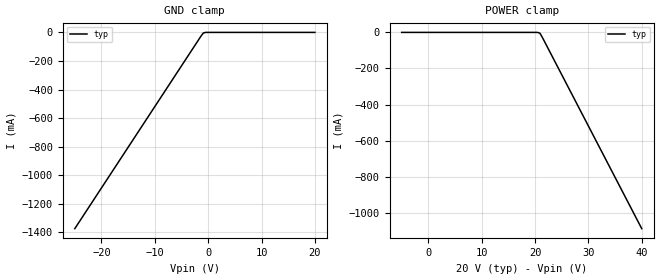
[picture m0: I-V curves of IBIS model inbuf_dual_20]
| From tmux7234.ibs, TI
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| inbuf_dual_20
[Model]   inbuf_dual_20
Model_type   Input
|   typ   min   max
C_comp   6.362683e-13   NA   NA
[Voltage Range]   20   NA   NA
[Temperature Range]   27   NA   NA
[Power Clamp Reference]   20   NA   NA
[GND Clamp Reference]   0   NA   NA
[GND Clamp]
|   Voltage   I(typ)   I(min)   I(max)
-25V      -1.374A    NA         NA
-1.364V   -27.16mA   NA         NA
-909.1mV  -4.356mA   NA         NA
-454.5mV  -3.664uA   NA         NA
20V       557nA      NA         NA
[POWER Clamp]
|   Voltage   I(typ)   I(min)   I(max)
-5V       557.3nA    NA         NA
20.45V    -3.664uA   NA         NA
20.91V    -4.356mA   NA         NA
21.36V    -27.16mA   NA         NA
40V       -1.088A    NA         NA
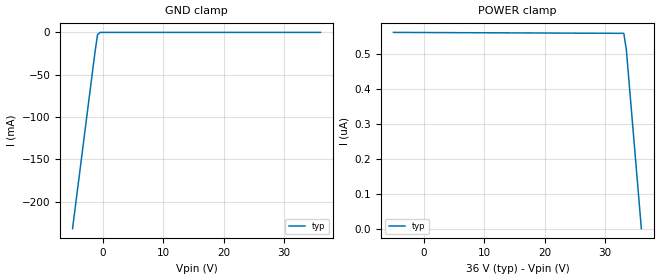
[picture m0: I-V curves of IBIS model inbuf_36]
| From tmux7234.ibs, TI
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| inbuf_36
[Model]   inbuf_36
Model_type   Input
|   typ   min   max
C_comp   4.014581e-13   NA   NA
[Voltage Range]   36   NA   NA
[Temperature Range]   27   NA   NA
[Power Clamp Reference]   36   NA   NA
[GND Clamp Reference]   0   NA   NA
[GND Clamp]
|   Voltage   I(typ)   I(min)   I(max)
-5V       -231.7mA   NA         NA
-1.273V   -22.3mA    NA         NA
-858.6mV  -2.503mA   NA         NA
-444.4mV  -3.056uA   NA         NA
36V       561.1nA    NA         NA
[POWER Clamp]
|   Voltage   I(typ)   I(min)   I(max)
-5V       561.5nA    NA         NA
33.1V     558.8nA    NA         NA
33.52V    511.5nA    NA         NA
36V       -173.7pA   NA         NA
